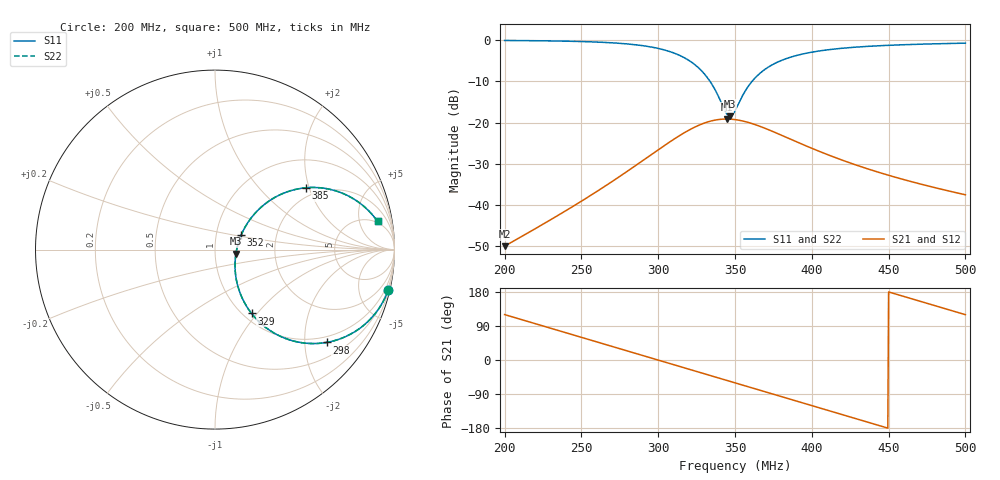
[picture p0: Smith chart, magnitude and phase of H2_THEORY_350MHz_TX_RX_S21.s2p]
! THEORETICAL_SURROGATE_ONLY - NOT VNA MEASUREMENT
! Ideal free-space 1.0 m broadside, co-polarized identical 350 MHz-centered dipoles
! S21 magnitude from Friis + dipole directivity + 50-ohm mismatch; phase=-kR only
! 601 points, 200-500 MHz, 50-ohm reference
# Hz S RI R 50
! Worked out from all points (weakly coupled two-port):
!   601 points, 200 MHz to 500 MHz, reference 50 ohm
!   highest |S21| = -19.13 dB at 344.5 MHz (marker M1); lowest = -50.0 dB at 200 MHz (marker M2)
!   lowest |S11| = -18.5 dB at 346.5 MHz (marker M3), VSWR 1.27, Z = 63.1 - j2.94 ohm
!   |S11| at or under -10 dB: 333.7 MHz to 361.1 MHz (27.35 MHz wide, 7.87 % of centre)
!   |S22| runs from -18.5 to -0.1 dB; largest |S21 - S12| = 0
!   S11 on the Smith chart (normalised r, x): 200 MHz: 0.33, -8.62; 298 MHz: 0.84, -2.52; 329 MHz: 1.09, -0.94; 352 MHz: 1.32, +0.22; 385 MHz: 1.72, +1.90; 500 MHz: 5, +9
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2e8  0.965 -0.2266  -0.00158 0.00276  -0.00158 0.00276  0.965 -0.2266
2.5e8  0.8943 -0.3541  0.00561 0.00964  0.00561 0.00964  0.8943 -0.3541
2.77e8  0.789 -0.451  0.021 0.0109  0.021 0.0109  0.789 -0.451
2.98e8  0.6213 -0.5172  0.0441 0.00166  0.0441 0.00166  0.6213 -0.5172
3e8  0.5994 -0.5204  0.0468 -0.000204  0.0468 -0.000204  0.5994 -0.5204
3.155e8  0.3939 -0.4956  0.0687 -0.0235  0.0687 -0.0235  0.3939 -0.4956
3.23e8  0.2835 -0.4345  0.0767 -0.0406  0.0767 -0.0406  0.2835 -0.4345
3.29e8  0.2038 -0.3558  0.0796 -0.0559  0.0796 -0.0559  0.2038 -0.3558
3.36e8  0.1367 -0.2338  0.0772 -0.0732  0.0772 -0.0732  0.1367 -0.2338
3.445e8  0.1124 -0.0629  0.0655 -0.0891  0.0655 -0.0891  0.1124 -0.0629
3.465e8  0.1165 -0.023  0.0616 -0.0916  0.0616 -0.0916  0.1165 -0.023
3.48e8  0.122 0.00627  0.0584 -0.0931  0.0584 -0.0931  0.122 0.00627
3.5e8  0.1322 0.044  0.0539 -0.0945  0.0539 -0.0945  0.1322 0.044
3.52e8  0.1454 0.0798  0.0493 -0.0955  0.0493 -0.0955  0.1454 0.0798
3.585e8  0.2047 0.1807  0.0336 -0.095  0.0336 -0.095  0.2047 0.1807
3.655e8  0.2851 0.2593  0.0176 -0.0895  0.0176 -0.0895  0.2851 0.2593
3.74e8  0.387 0.3162  0.00123 -0.0789  0.00123 -0.0789  0.387 0.3162
3.85e8  0.5054 0.3444  -0.0137 -0.0629  -0.0137 -0.0629  0.5054 0.3444
4e8  0.6297 0.3381  -0.0247 -0.0422  -0.0247 -0.0422  0.6297 0.3381
4.22e8  0.7475 0.2966  -0.0284 -0.0186  -0.0284 -0.0186  0.7475 0.2966
4.5e8  0.8322 0.2387  -0.023 0.00015  -0.023 0.00015  0.8322 0.2387
5e8  0.9055 0.1576  -0.00659 0.0116  -0.00659 0.0116  0.9055 0.1576
